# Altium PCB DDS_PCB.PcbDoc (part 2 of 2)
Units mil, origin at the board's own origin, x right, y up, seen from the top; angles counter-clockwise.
Board outline 3998.07 x 3476.44 mil, 8 copper layers (TOP_L1, Plane_L2, Inner_L3, Plane_L4, Plane_L5, Inner_L6, Plane_L7, Bottom Layer_L8), stack 26.8 mil thick; 448 components, 265 nets, 1489 pads, 18 vias.
Unrouted connection lines stored in the file: 996.

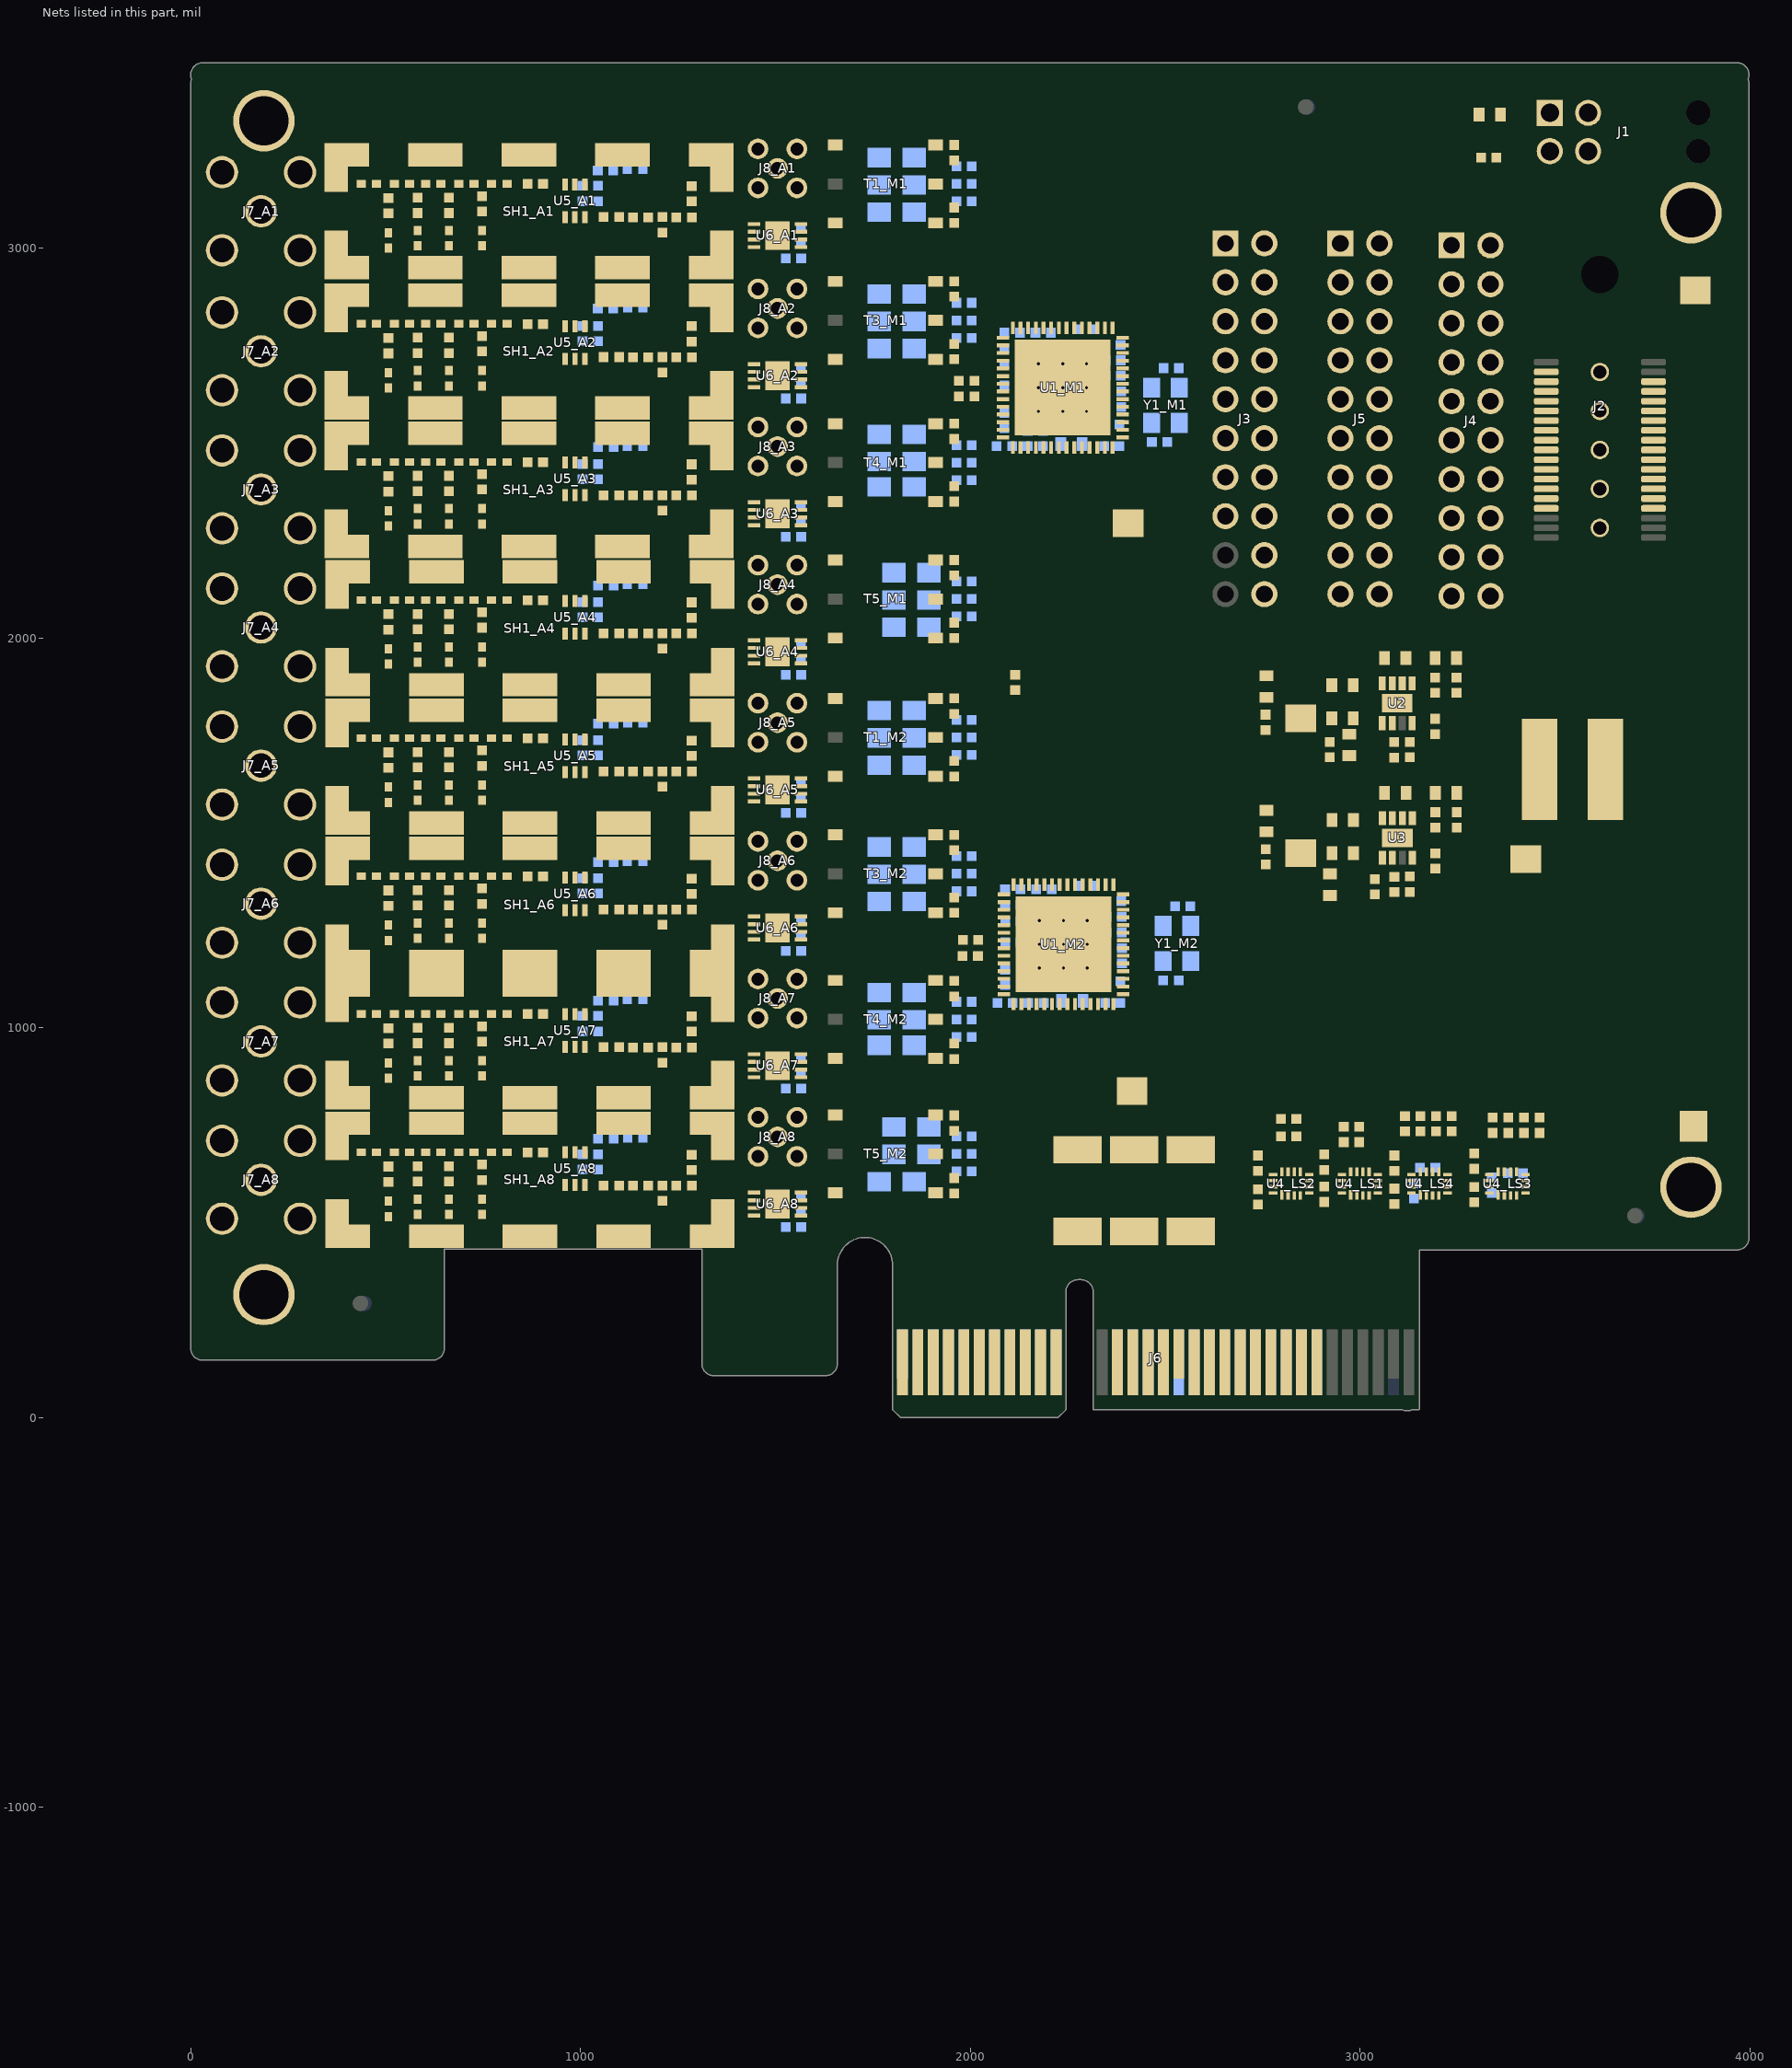
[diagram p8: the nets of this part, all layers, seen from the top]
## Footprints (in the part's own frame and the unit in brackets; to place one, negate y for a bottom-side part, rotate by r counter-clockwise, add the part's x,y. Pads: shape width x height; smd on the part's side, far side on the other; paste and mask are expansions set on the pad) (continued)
PCIE_8LANE_EDGE [mil] "PCIE_8LANE_EDGE"
  rect 28x126 smd far side paste-100: A1(-984.25,-93.98)
  rect 28x169 smd far side paste-100: A2(-944.88,-115.48) A3(-905.51,-115.48) A4(-866.14,-115.48) A5(-826.77,-115.48) A6(-787.4,-115.48) A7(-748.03,-115.48) A8(-708.66,-115.48) A9(-669.29,-115.48) A10(-629.92,-115.48) A11(-590.55,-115.48) A12(-472.44,-115.48) A13(-433.07,-115.48) A14(-393.7,-115.48) A15(-354.33,-115.48) A16(-314.96,-115.48) A17(-275.59,-115.48) A18(-236.22,-115.48) A19(-196.85,-115.48) A20(-157.48,-115.48) A21(-118.11,-115.48) A22(-78.74,-115.48) A23(-39.37,-115.48) A24(0,-115.48) A25(39.37,-115.48) A26(78.74,-115.48) A27(118.11,-115.48) A28(157.48,-115.48) A29(196.85,-115.48) A30(236.22,-115.48) A31(275.59,-115.48) A32(314.96,-115.48)
  rect 28x169 smd paste-100 mask+2: B1(-984.25,-115.48) B2(-944.88,-115.48) B3(-905.51,-115.48) B4(-866.14,-115.48) B5(-826.77,-115.48) B6(-787.4,-115.48) B7(-748.03,-115.48) B8(-708.66,-115.48) B9(-669.29,-115.48) B10(-629.92,-115.48) B11(-590.55,-115.48) B12(-472.44,-115.48) B13(-433.07,-115.48) B14(-393.7,-115.48) B15(-354.33,-115.48) B16(-314.96,-115.48) B18(-236.22,-115.48) B19(-196.85,-115.48) B20(-157.48,-115.48) B21(-118.11,-115.48) B22(-78.74,-115.48) B23(-39.37,-115.48) B24(0,-115.48) B25(39.37,-115.48) B26(78.74,-115.48) B27(118.11,-115.48) B28(157.48,-115.48) B29(196.85,-115.48) B30(236.22,-115.48) B32(314.96,-115.48)
  rect 28x126 smd paste-100 mask+2: B17(-275.59,-93.98) B31(275.59,-93.98)
R0402 [mil] "R0402"
  rect 25x25 smd mask+2: 1(-18.5,0) 2(20.9,0)
  silkscreen extent -36,-17 40,17, body extent -20,-10 20,10, height 14
r0402 [mil] "R0402"
  rect 25x25 smd mask+2: 1(-18.5,0) 2(20.9,0)
  silkscreen extent -36,-17 40,17, body extent -20,-10 20,10, height 14
R0805 [mil] "R0805"
  rect 60x50 smd mask+2: 1(-45,0) 2(45,0)
  silkscreen extent -80,-30 80,30, body extent -39,-25 39,24, height 31
RF_Sh [mil]
  rect 60x125 smd mask+2: 1(-495,-112.5) 1(-495,112.5) 1(495,-112.5) 1(495,112.5)
  rect 115x60 smd mask+2: 1(-467.5,-145) 1(-467.5,145) 1(467.5,-145) 1(467.5,145)
  rect 140x60 smd mask+2: 1(-240,-145) 1(-240,145) 1(0,-145) 1(0,145) 1(240,-145) 1(240,145)
SAMTEC_MMCX-J-P-H-ST-TH1 [mm]
  round 1.348 hole 0.84: 1(0,0) S1(-1.27,1.27) S2(1.27,1.27) S3(1.27,-1.27) S4(-1.27,-1.27)
  silkscreen extent -1.75,-1.75 1.75,1.75, body extent -1.75,-1.75 1.75,1.75, height 4.35
SMD4_ECX-32_3P2X2P5_ECS [mm]
  rect 1.1x1.3 smd paste-0.55 mask+0.051: 1(-0.9,1.15) 2(-0.9,-1.15) 3(0.9,-1.15) 4(0.9,1.15)
  silkscreen extent -1.42,-0.17 1.42,0.17, body extent -1.3,-1.65 1.3,1.65, height 0.81
SO8_MUN12AD_DEA [mm]
  rect 0.91x0.458 smd paste+0 mask+0.051: 1(-1.293,0.975) 2(-1.293,0.325) 3(-1.293,-0.325) 4(-1.293,-0.975) 5(1.293,-0.975) 6(1.293,-0.325) 7(1.293,0.325) 8(1.293,0.975)
  rect 1.2x2 smd paste+0 mask+0.051: 9(0,0)
  silkscreen extent -1.57,-1.68 1.57,1.68, body extent -1.45,-1.55 1.45,1.55, height 1.5
SOT_2815,115_NXP [mm]
  rect 0.782x0.355 smd paste+0 mask+0.051: 1(-1.064,0.65) 2(-1.064,0) 3(-1.064,-0.65) 4(1.064,-0.65) 5(1.064,0) 6(1.064,0.65)
  silkscreen extent -0.8,-1.23 0.8,1.23, body extent -1.1,-1.1 1.1,1.1, height 1.09
TP_2X1.8 [mm]
  rect 1.8x2 smd mask+0.051: 1(0,0)
  body extent -0.89,-0.99 0.89,0.99, height 0.03

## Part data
C1_M1 C1_M2: library part "CAP CER 6.8pF 50V NP0 0402", "CAP CER 680PF 50V NP0 0402", Capacitance=680pF, Manufacturer="TDK Corporation", Manufacturer Part Number=C1005C0G1H6R8D, Package / Case="0402 (1005 Metric)", Voltage - Rated=50V
C2_M1 C2_M2 C3_M1 C3_M2: library part "CAP CER 6.8pF 50V NP0 0402", "CAP CER 39PF 50V NP0 0402", Capacitance=39pF, Manufacturer="TDK Corporation", Manufacturer Part Number=C1005C0G1H6R8D, Package / Case="0402 (1005 Metric)", Voltage - Rated=50V
C4_M1 C4_M2 C5_M1 C5_M2 C6_M1 C6_M2 C31_A1 C31_A2 C31_A3 C31_A4 C31_A5 C31_A6 C31_A7 C31_A8 C32_A1 C32_A2 C32_A3 C32_A4 C32_A5 C32_A6 C32_A7 C32_A8 C40_A1 C40_A2 C40_A3 C40_A4 C40_A5 C40_A6 C40_A7 C40_A8: library part "CAP CER 6.8pF 50V NP0 0402", "CAP CER 1uF 25V X5R 0402", Capacitance=1uF, Manufacturer="TDK Corporation", Manufacturer Part Number=C1005C0G1H6R8D, Package / Case="0402 (1005 Metric)", Voltage - Rated=50V
C7_M1 C7_M2 C8_M1 C8_M2 C9_M1 C9_M2 C43_M1 C43_M2 C59_M1 C59_M2 C62_M1 C62_M2 C65_M1 C65_M2: library part "CAP CER 6.8pF 50V NP0 0402", "CAP CER 10uF 10V X5R 0402", Capacitance=10uF, Manufacturer="TDK Corporation", Manufacturer Part Number=C1005C0G1H6R8D, Package / Case="0402 (1005 Metric)", Voltage - Rated=50V
C10_M1 C10_M2 C11_M1 C11_M2 C12_M1 C12_M2 C29_LS1 C29_LS2 C29_LS3 C29_LS4 C30_LS1 C30_LS2 C30_LS3 C30_LS4 C38_A1 C38_A2 C38_A3 C38_A4 C38_A5 C38_A6 C38_A7 C38_A8 C39_A1 C39_A2 C39_A3 C39_A4 C39_A5 C39_A6 C39_A7 C39_A8 C41_M1 C41_M2 C42_M1 C42_M2 C57_M1 C57_M2 C58_M1 C58_M2 C60_M1 C60_M2 C61_M1 C61_M2 C63_M1 C63_M2 C64_M1 C64_M2: library part "CAP CER 6.8pF 50V NP0 0402", "CAP CER 0.1uF 50V NP0 0402", Capacitance=0.1uF, Manufacturer="TDK Corporation", Manufacturer Part Number=C1005C0G1H6R8D, Package / Case="0402 (1005 Metric)", Voltage - Rated=50V
C13 C20 C26: library part "CAP CER 10uF 10V 10% X5R 0603", "CAP CER 10UF 25V 10% X5R 0603", Capacitance=10µF, Manufacturer="TDK Corporation", Manufacturer Part Number=C1608X5R1A106K, Package / Case="0603 (1608 Metric)", Voltage - Rated=10V
C14 C15 C18 C19 C22 C24 C25: library part "CAP CER 12nF 25V 10% X7R 0402", "CAP CER 10nF 25V 10% X5R 0402", Capacitance=10nF, Manufacturer="Murata Electronics North America", Manufacturer Part Number=GRM155R71E123KA61D, Package / Case="0402 (1005 Metric)", Voltage - Rated=25V
C16 C17 C23 C27: library part "CAP CER 10uF 10V 10% X5R 0603", "CAP CER 22UF 16V 10% X5R 0603", Capacitance=22µF, Manufacturer="TDK Corporation", Manufacturer Part Number=C1608X5R1A106K, Package / Case="0603 (1608 Metric)", Voltage - Rated=10V
C21 C28: library part "CAP CER 6.8pF 50V NP0 0402", "CAP CER NA 50V NP0 0402", Manufacturer="TDK Corporation", Manufacturer Part Number=C1005C0G1H6R8D, Package / Case="0402 (1005 Metric)", Voltage - Rated=50V
C33_A1 C33_A2 C33_A3 C33_A4 C33_A5 C33_A6 C33_A7 C33_A8: library part "CAP CER 20pF 50V 5% NP0 0402", "CAP CER 16PF 50V 5% NP0 0402", Capacitance=16pF, Manufacturer="TDK Corporation", Manufacturer Part Number=C1005C0G1H200J, Package / Case="0402 (1005 Metric)", Voltage - Rated=50V
C34_A1 C34_A2 C34_A3 C34_A4 C34_A5 C34_A6 C34_A7 C34_A8: library part "CAP CER 20pF 50V 5% NP0 0402", "CAP CER 11PF 50V 5% NP0 0402", Capacitance=11pF, Manufacturer="TDK Corporation", Manufacturer Part Number=C1005C0G1H200J, Package / Case="0402 (1005 Metric)", Voltage - Rated=50V
C35_A1 C35_A2 C35_A3 C35_A4 C35_A5 C35_A6 C35_A7 C35_A8: library part "CAP CER 20pF 50V 5% NP0 0402", "CAP CER 10PF 50V 5% NP0 0402", Capacitance=10pF, Manufacturer="TDK Corporation", Manufacturer Part Number=C1005C0G1H200J, Package / Case="0402 (1005 Metric)", Voltage - Rated=50V
C36_A1 C36_A2 C36_A3 C36_A4 C36_A5 C36_A6 C36_A7 C36_A8: library part "CAP CER 20pF 50V 5% NP0 0402", "CAP CER 13PF 50V 5% NP0 0402", Capacitance=13pF, Manufacturer="TDK Corporation", Manufacturer Part Number=C1005C0G1H200J, Package / Case="0402 (1005 Metric)", Voltage - Rated=50V
C37_A1 C37_A2 C37_A3 C37_A4 C37_A5 C37_A6 C37_A7 C37_A8: library part "CAP CER 6.8pF 50V NP0 0402", "CAP CER 470pF 25V X5R 0402", Capacitance=470pF, Manufacturer="TDK Corporation", Manufacturer Part Number=C1005C0G1H6R8D, Package / Case="0402 (1005 Metric)", Voltage - Rated=50V
F1 F2 F3: library part 1812L150/24MR, "FUSE PTC 24V 1.5A POLYFUSE 1812", Current - Hold (Ih) (Max)=1.5A, Manufacturer="Littelfuse Inc", Package / Case="1812 (4532 Metric), Concave"
FB1_M1 FB1_M2 FB2 FB3 FB4 FB5: library part BK1608HS600-T, "FERRITE BEAD 220_OHM@100MHz 0603 2A 50mohm_DC", Manufacturer="Taiyo Yuden", Package / Case="0603 (1608 Metric)"
FB6_A1 FB6_A2 FB6_A3 FB6_A4 FB6_A5 FB6_A6 FB6_A7 FB6_A8: library part BK1608HS600-T, "FERRITE BEAD 1.8K OHM 0402 1LN", Manufacturer="Taiyo Yuden", Package / Case="0603 (1608 Metric)"
H1 H2 H3 H4: "hole 3mm"
J1: "No Description Available", Mfr_Name="Molex Connector Corporation"
J2: "CONN MICTOR 38POS .025 VERT SMD", Manufacturer="TE Connectivity"
J3 J4 J5: "CONN HEADER 20 TH", Manufacturer="Molex Connector Corporation"
J6: "64 Position Female Connector PCI Expressâ„¢ Gold 0.039 _1.00mm_ Black", Package=None
J7_A1 J7_A2 J7_A3 J7_A4 J7_A5 J7_A6 J7_A7 J7_A8: "No Description Available", Mfr_Name="Samtec Inc"
J8_A1 J8_A2 J8_A3 J8_A4 J8_A5 J8_A6 J8_A7 J8_A8: "MMCX STRAIGHT, THROUGH HOLE JACK- 50 OHM", Package=None
LD1 LD2: "LED 1.6X0.8MM 568NM GRN CLR SMD", Manufacturer="Kingbright Corp", Package / Case="0603 (1608 Metric)"
Lp1: "INDUCTOR 10UH 1.9A 20% SMD", Manufacturer="Taiyo Yuden", Package / Case="Non Standard"
R1_M1 R1_M2: library part "RES 3.09K OHM 1/16W 1% 0402", "RES 6.8K OHM 1/16W 1% 0402", Manufacturer="Stackpole Electronics Inc", Manufacturer Part Number=RMCF0402FT3K09, Package / Case="0402 (1005 Metric)", Power (Watts)="0.063W, 1/16W", Supplier Device Package=0402
R2_M1 R2_M2 R7_M1 R7_M2 R8_M1 R8_M2 R9_M1 R9_M2 R10_M1 R10_M2 R33 R41_A1 R41_A2 R41_A3 R41_A4 R41_A5 R41_A6 R41_A7 R41_A8: library part "RES 100 OHM 1/10W 1% 0402 SMD", "RES 0 OHM 1/10W 1% 0402 SMD", Manufacturer="Panasonic Electronic Components", Manufacturer Part Number=ERJ-2RKF1000X, Package / Case="0402 (1005 Metric)", Supplier Device Package=0402
R3_M1 R3_M2 R4_M1 R4_M2 R5_M1 R5_M2 R6_M1 R6_M2 R11_M1 R11_M2 R12_M1 R12_M2 R13_M1 R13_M2 R14_M1 R14_M2: library part "RES 3.09K OHM 1/16W 1% 0402", "RES 10K OHM 1/16W 1% 0402", Manufacturer="Stackpole Electronics Inc", Manufacturer Part Number=RMCF0402FT3K09, Package / Case="0402 (1005 Metric)", Power (Watts)="0.063W, 1/16W", Supplier Device Package=0402
R15_M1 R15_M2 R16_M1 R16_M2 R17_M1 R17_M2 R18_M1 R18_M2 R19_M1 R19_M2 R20_M1 R20_M2 R21_M1 R21_M2 R22_M1 R22_M2 R23_M1 R23_M2 R24_M1 R24_M2 R25_M1 R25_M2 R26_M1 R26_M2: library part "RES 200 OHM 1/8W 1% 0805 SMD", "RES 0 OHM 1/8W 1% 0805 SMD", Manufacturer="Stackpole Electronics Inc", Manufacturer Part Number=RMCF0805FT200R, Package / Case="0805 (2012 Metric)", Power (Watts)="0.125W, 1/8W", Supplier Device Package=0805
R27 R30: library part "RES 15.4K OHM 1/10W 1% 0402 SMD", "RES 124K OHM 1/10W 1% 0402 SMD", Manufacturer="Panasonic Electronic Components", Manufacturer Part Number=ERJ-2RKF1542X, Package / Case="0402 (1005 Metric)", Power (Watts)="0.1W, 1/10W", Supplier Device Package=0402
R28 R31: library part "RES 3.09K OHM 1/16W 1% 0402", "RES 1K OHM 1/16W 1% 0402", Manufacturer="Stackpole Electronics Inc", Manufacturer Part Number=RMCF0402FT3K09, Package / Case="0402 (1005 Metric)", Power (Watts)="0.063W, 1/16W", Supplier Device Package=0402
R29: library part "RES 15.4K OHM 1/10W 1% 0402 SMD", "RES 39.2K OHM 1/10W 1% 0402 SMD", Manufacturer="Panasonic Electronic Components", Manufacturer Part Number=ERJ-2RKF1542X, Package / Case="0402 (1005 Metric)", Power (Watts)="0.1W, 1/10W", Supplier Device Package=0402
R32 R34_LS1 R34_LS2 R34_LS3 R34_LS4: library part "RES 3.09K OHM 1/16W 1% 0402", "RES 100K OHM 1/16W 1% 0402", Manufacturer="Stackpole Electronics Inc", Manufacturer Part Number=RMCF0402FT3K09, Package / Case="0402 (1005 Metric)", Power (Watts)="0.063W, 1/16W", Supplier Device Package=0402
R35_LS1 R35_LS2 R35_LS3 R35_LS4: library part "RES 3.09K OHM 1/16W 1% 0402", "RES 3.09K OHM 1/16W 1% 0402", Manufacturer="Stackpole Electronics Inc", Manufacturer Part Number=RMCF0402FT3K09, Package / Case="0402 (1005 Metric)", Power (Watts)="0.063W, 1/16W", Supplier Device Package=0402
R36_A1 R36_A2 R36_A3 R36_A4 R36_A5 R36_A6 R36_A7 R36_A8 R37_A1 R37_A2 R37_A3 R37_A4 R37_A5 R37_A6 R37_A7 R37_A8: library part "RES 100 OHM 1/10W 1% 0402 SMD", "RES 34.8 OHM 1/10W 1% 0402 SMD", Manufacturer="Panasonic Electronic Components", Manufacturer Part Number=ERJ-2RKF1000X, Package / Case="0402 (1005 Metric)", Supplier Device Package=0402
R38_A1 R38_A2 R38_A3 R38_A4 R38_A5 R38_A6 R38_A7 R38_A8 R42_A1 R42_A2 R42_A3 R42_A4 R42_A5 R42_A6 R42_A7 R42_A8: library part "RES 100 OHM 1/10W 1% 0402 SMD", "RES 18.2 OHM 1/10W 1% 0402 SMD", Manufacturer="Panasonic Electronic Components", Manufacturer Part Number=ERJ-2RKF1000X, Package / Case="0402 (1005 Metric)", Supplier Device Package=0402
R39_M1 R39_M2 R40_M1 R40_M2 R50_M1 R50_M2 R51_M1 R51_M2 R52_M1 R52_M2 R53_M1 R53_M2 R54_M1 R54_M2 R55_M1 R55_M2: library part "RES 100 OHM 1/10W 1% 0402 SMD", "RES 49.9 OHM 1/10W 1% 0402 SMD", Manufacturer="Panasonic Electronic Components", Manufacturer Part Number=ERJ-2RKF1000X, Package / Case="0402 (1005 Metric)", Supplier Device Package=0402
SH1_A1 SH1_A2 SH1_A3 SH1_A4 SH1_A5 SH1_A6 SH1_A7 SH1_A8: library part RF_SHIELD_1, "RF Shield Cover 0.300\" (7.62mm) X 1.000\" (25.40mm) Non-Vented Surface Mount", Manufacturer="Orbel Corporation"
T1_M1 T1_M2 T3_M1 T3_M2 T4_M1 T4_M2 T5_M1 T5_M2: "No Description Available", Mfr_Name="Mini Circuits"
TP1 TP2 TP3 TP4 TP5 TP6: library part "TP mini_2", "TP PC MINIATURE SMT", Manufacturer="Keystone Electronics", Manufacturer Part Number=5015
TP7: library part "TP mini_1", "TP PC MINIATURE SMT", Manufacturer="Keystone Electronics", Manufacturer Part Number=5015
U1_M1 U1_M2 U6_A1 U6_A2 U6_A3 U6_A4 U6_A5 U6_A6 U6_A7 U6_A8: "No Description Available", Mfr_Name="Analog Devices Inc"
U2 U3: "No Description Available", Mfr_Name=Delta
U5_A1 U5_A2 U5_A3 U5_A4 U5_A5 U5_A6 U5_A7 U5_A8: "No Description Available", Mfr_Name=NXP
Y1_M1 Y1_M2: "No Description Available", Mfr_Name="ECS International"

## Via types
v1: diameter 16, hole 8, TOP_L1 to Bottom Layer_L8, tented both sides, 18 vias

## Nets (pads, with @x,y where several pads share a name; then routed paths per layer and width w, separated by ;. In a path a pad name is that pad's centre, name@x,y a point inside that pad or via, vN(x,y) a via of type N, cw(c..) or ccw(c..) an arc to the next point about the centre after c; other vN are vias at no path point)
1.8V: C23.2 C27.2 FB5.1 R30.2 U3.4 U3.5
1_8V: F2.1 J6.B5 J6.B6 J6.B7 J6.B8
3.3V: C16.2 C17.2 FB3.1 R27.2 U2.4 U2.5
3.3V_AMP_A1: C37_A1.2 C38_A1.2 R42_A1.2 U5_A1.1
3.3V_AMP_A2: C37_A2.2 C38_A2.2 R42_A2.2 U5_A2.1
3.3V_AMP_A3: C37_A3.2 C38_A3.2 R42_A3.2 U5_A3.1
3.3V_AMP_A4: C37_A4.2 C38_A4.2 R42_A4.2 U5_A4.1
3.3V_AMP_A5: C37_A5.2 C38_A5.2 R42_A5.2 U5_A5.1
3.3V_AMP_A6: C37_A6.2 C38_A6.2 R42_A6.2 U5_A6.1
3.3V_AMP_A7: C37_A7.2 C38_A7.2 R42_A7.2 U5_A7.1
3.3V_AMP_A8: C37_A8.2 C38_A8.2 R42_A8.2 U5_A8.1
3_3V: F1.1 J6.B1 J6.B2 J6.B3 J6.B4
12_V: F3.2 J6.A1 J6.A2 J6.A3 J6.A4
12v_1: C19.2 C20.2 FB2.2 U2.1 U2.2
12v_2: C25.2 C26.2 FB4.2 U3.1 U3.2
12v_in: C13.2 C14.2 J1.1 J1.2 Lp1.1
AVDD0_M1: C41_M1.2 C42_M1.2 C43_M1.2 R18_M1.2 R22_M1.2 R26_M1.2 R39_M1.2 R40_M1.1 T1_M1.2
AVDD0_M2: C41_M2.2 C42_M2.2 C43_M2.2 R18_M2.2 R22_M2.2 R26_M2.2 R39_M2.2 R40_M2.1 T1_M2.2
AVDD1_M1: C57_M1.2 C58_M1.2 C59_M1.2 R17_M1.2 R18_M1.1 R21_M1.2 R22_M1.1 R25_M1.2 R26_M1.1 R50_M1.2 R51_M1.1 T3_M1.2
AVDD1_M2: C57_M2.2 C58_M2.2 C59_M2.2 R17_M2.2 R18_M2.1 R21_M2.2 R22_M2.1 R25_M2.2 R26_M2.1 R50_M2.2 R51_M2.1 T3_M2.2
AVDD2_M1: C60_M1.2 C61_M1.2 C62_M1.2 R16_M1.2 R17_M1.1 R20_M1.2 R21_M1.1 R24_M1.2 R25_M1.1 R52_M1.2 R53_M1.1 T4_M1.2
AVDD2_M2: C60_M2.2 C61_M2.2 C62_M2.2 R16_M2.2 R17_M2.1 R20_M2.2 R21_M2.1 R24_M2.2 R25_M2.1 R52_M2.2 R53_M2.1 T4_M2.2
AVDD3_M1: C63_M1.2 C64_M1.2 C65_M1.2 R15_M1.2 R16_M1.1 R19_M1.2 R20_M1.1 R23_M1.2 R24_M1.1 R54_M1.2 R55_M1.1 T5_M1.2
AVDD3_M2: C63_M2.2 C64_M2.2 C65_M2.2 R15_M2.2 R16_M2.1 R19_M2.2 R20_M2.1 R23_M2.2 R24_M2.1 R54_M2.2 R55_M2.1 T5_M2.2
CH0_M1_N: R40_M1.2 T1_M1.3 U1_M1.29
CH0_M1_P: R39_M1.1 T1_M1.1 U1_M1.30
CH0_M2_N: R40_M2.2 T1_M2.3 U1_M2.29
CH0_M2_P: R39_M2.1 T1_M2.1 U1_M2.30
CH1_M1_N: R51_M1.2 T3_M1.3 U1_M1.35
CH1_M1_P: R50_M1.1 T3_M1.1 U1_M1.36
CH1_M2_N: R51_M2.2 T3_M2.3 U1_M2.35
CH1_M2_P: R50_M2.1 T3_M2.1 U1_M2.36
CH2_M1_N: R53_M1.2 T4_M1.1 U1_M1.9
CH2_M1_P: R52_M1.1 T4_M1.3 U1_M1.8
CH2_M2_N: R53_M2.2 T4_M2.1 U1_M2.9
CH2_M2_P: R52_M2.1 T4_M2.3 U1_M2.8
CH3_M1_N: R55_M1.2 T5_M1.1 U1_M1.14
CH3_M1_P: R54_M1.1 T5_M1.3 U1_M1.13
CH3_M2_N: R55_M2.2 T5_M2.1 U1_M2.14
CH3_M2_P: R54_M2.1 T5_M2.3 U1_M2.13
CLK_sel_M1: R8_M1.1 R10_M1.2 U1_M1.24
CLK_sel_M2: R8_M2.1 R10_M2.2 U1_M2.24
contr0_M1: J2.26 J3.1 J6.B13 U6_A1.2
contr0_M2: J2.25 J3.9 J6.A13 U6_A5.2
contr1_M1: J2.28 J3.3 J6.B14 U6_A2.2
contr1_M2: J2.27 J3.11 J6.A14 U6_A6.2
contr2_M1: J2.30 J3.5 J6.B15 U6_A3.2
contr2_M2: J2.29 J3.13 J6.A15 U6_A7.2
contr3_M1: J2.32 J3.7 J6.B16 U6_A4.2
contr3_M2: J2.31 J3.15 J6.A16 U6_A8.2
CSn: U1_M1.47 U4_LS2.12
CSn_2: U1_M2.47 U4_LS1.12
CSn_2_L: J2.7 J5.3 J6.A18 U4_LS1.1
CSn_L: J2.8 J4.3 J6.B18 U4_LS2.1
DAC_O0_M1: T1_M1.6 U6_A1.4
DAC_O0_M2: T1_M2.6 U6_A5.4
DAC_O1_M1: T3_M1.6 U6_A2.4
DAC_O1_M2: T3_M2.6 U6_A6.4
DAC_O2_M1: T4_M1.4 U6_A3.4
DAC_O2_M2: T4_M2.4 U6_A7.4
DAC_O3_M1: T5_M1.4 U6_A4.4
DAC_O3_M2: T5_M2.4 U6_A8.4
DIR_LS1: J2.21 J5.17 J6.A25 R34_LS1.1 R34_LS4.1 R35_LS1.2 R35_LS4.2 U4_LS1.5 U4_LS1.6 U4_LS1.15 U4_LS1.16 U4_LS4.5 U4_LS4.6 U4_LS4.15 U4_LS4.16
DIR_LS2: J2.22 J4.17 J6.B25 R34_LS2.1 R34_LS3.1 R35_LS2.2 R35_LS3.2 U4_LS2.5 U4_LS2.6 U4_LS2.15 U4_LS2.16 U4_LS3.5 U4_LS3.6 U4_LS3.15 U4_LS3.16
FB_1.8: R30.1 R32.2 U3.6
FB_3.3: R27.1 R29.2 U2.6
GND: C2_M1.2 C2_M2.2 C3_M1.1 C3_M2.1 C4_M1.1 C4_M2.1 C5_M1.1 C5_M2.1 C6_M1.1 C6_M2.1 C7_M1.1 C7_M2.1 C8_M1.1 C8_M2.1 C9_M1.1 C9_M2.1 C10_M1.1 C10_M2.1 C11_M1.1 C11_M2.1 C12_M1.1 C12_M2.1 C13.1 C14.1 C15.1 C16.1 C17.1 C18.1 C19.1 C20.1 C21.1 C22.1 C23.1 C24.1 C25.1 C26.1 C27.1 C28.1 C29_LS1.1 C29_LS2.1 C29_LS3.1 C29_LS4.1 C30_LS1.1 C30_LS2.1 C30_LS3.1 C30_LS4.1 C37_A1.1 C37_A2.1 C37_A3.1 C37_A4.1 C37_A5.1 C37_A6.1 C37_A7.1 C37_A8.1 C38_A1.1 C38_A2.1 C38_A3.1 C38_A4.1 C38_A5.1 C38_A6.1 C38_A7.1 C38_A8.1 C39_A1.1 C39_A2.1 C39_A3.1 C39_A4.1 C39_A5.1 C39_A6.1 C39_A7.1 C39_A8.1 C40_A1.1 C40_A2.1 C40_A3.1 C40_A4.1 C40_A5.1 C40_A6.1 C40_A7.1 C40_A8.1 C41_M1.1 C41_M2.1 C42_M1.1 C42_M2.1 C43_M1.1 C43_M2.1 C57_M1.1 C57_M2.1 C58_M1.1 C58_M2.1 C59_M1.1 C59_M2.1 C60_M1.1 C60_M2.1 C61_M1.1 C61_M2.1 C62_M1.1 C62_M2.1 C63_M1.1 C63_M2.1 C64_M1.1 C64_M2.1 C65_M1.1 C65_M2.1 H1.1 H2.1 H3.1 H4.1 J1.3 J1.4 J2.3 J2.39 J2.40 J2.41 J2.42 J2.43 J3.2 J3.4 J3.6 J3.8 J3.10 J3.12 J3.14 J3.16 J3.18 J3.20 J4.2 J4.4 J4.6 J4.8 J4.10 J4.12 J4.14 J4.16 J4.18 J4.20 J5.2 J5.4 J5.6 J5.8 J5.10 J5.12 J5.14 J5.16 J5.18 J5.20 J6.A5 J6.A6 J6.A7 J6.A8 J6.A9 J6.A10 J6.A11 J6.B9 J6.B10 J6.B11 J7_A1.2 J7_A1.3 J7_A1.4 J7_A1.5 J7_A2.2 J7_A2.3 J7_A2.4 J7_A2.5 J7_A3.2 J7_A3.3 J7_A3.4 J7_A3.5 J7_A4.2 J7_A4.3 J7_A4.4 J7_A4.5 J7_A5.2 J7_A5.3 J7_A5.4 J7_A5.5 J7_A6.2 J7_A6.3 J7_A6.4 J7_A6.5 J7_A7.2 J7_A7.3 J7_A7.4 J7_A7.5 J7_A8.2 J7_A8.3 J7_A8.4 J7_A8.5 J8_A1.S1 J8_A1.S2 J8_A1.S3 J8_A1.S4 J8_A2.S1 J8_A2.S2 J8_A2.S3 J8_A2.S4 J8_A3.S1 J8_A3.S2 J8_A3.S3 J8_A3.S4 J8_A4.S1 J8_A4.S2 J8_A4.S3 J8_A4.S4 J8_A5.S1 J8_A5.S2 J8_A5.S3 J8_A5.S4 J8_A6.S1 J8_A6.S2 J8_A6.S3 J8_A6.S4 J8_A7.S1 J8_A7.S2 J8_A7.S3 J8_A7.S4 J8_A8.S1 J8_A8.S2 J8_A8.S3 J8_A8.S4 L6_A1.2 L6_A2.2 L6_A3.2 L6_A4.2 L6_A5.2 L6_A6.2 L6_A7.2 L6_A8.2 L7_A1.2 L7_A2.2 L7_A3.2 L7_A4.2 L7_A5.2 L7_A6.2 L7_A7.2 L7_A8.2 L8_A1.2 L8_A2.2 L8_A3.2 L8_A4.2 L8_A5.2 L8_A6.2 L8_A7.2 L8_A8.2 L9_A1.2 L9_A2.2 L9_A3.2 L9_A4.2 L9_A5.2 L9_A6.2 L9_A7.2 L9_A8.2 LD1.2 LD2.2 R1_M1.1 R1_M2.1 R3_M1.1 R3_M2.1 R4_M1.1 R4_M2.1 R5_M1.1 R5_M2.1 R6_M1.1 R6_M2.1 R9_M1.1 R9_M2.1 R10_M1.1 R10_M2.1 R11_M1.1 R11_M2.1 R12_M1.1 R12_M2.1 R13_M1.1 R13_M2.1 R14_M1.1 R14_M2.1 R29.1 R32.1 R35_LS1.1 R35_LS2.1 R35_LS3.1 R35_LS4.1 R38_A1.2 R38_A2.2 R38_A3.2 R38_A4.2 R38_A5.2 R38_A6.2 R38_A7.2 R38_A8.2 SH1_A1.1 SH1_A2.1 SH1_A3.1 SH1_A4.1 SH1_A5.1 SH1_A6.1 SH1_A7.1 SH1_A8.1 T1_M1.4 T1_M2.4 T3_M1.4 T3_M2.4 T4_M1.6 T4_M2.6 T5_M1.6 T5_M2.6 TP6.1 TP7.1 U1_M1.6 U1_M1.10 U1_M1.12 U1_M1.16 U1_M1.18 U1_M1.20 U1_M1.25 U1_M1.28 U1_M1.32 U1_M1.34 U1_M1.38 U1_M1.44 U1_M1.56 U1_M1.57 U1_M2.6 U1_M2.10 U1_M2.12 U1_M2.16 U1_M2.18 U1_M2.20 U1_M2.25 U1_M2.28 U1_M2.32 U1_M2.34 U1_M2.38 U1_M2.44 U1_M2.56 U1_M2.57 U2.3 U2.9 U3.3 U3.9 U4_LS1.7 U4_LS1.8 U4_LS2.7 U4_LS2.8 U4_LS3.7 U4_LS3.8 U4_LS4.7 U4_LS4.8 U5_A1.2 U5_A1.4 U5_A1.5 U5_A2.2 U5_A2.4 U5_A2.5 U5_A3.2 U5_A3.4 U5_A3.5 U5_A4.2 U5_A4.4 U5_A4.5 U5_A5.2 U5_A5.4 U5_A5.5 U5_A6.2 U5_A6.4 U5_A6.5 U5_A7.2 U5_A7.4 U5_A7.5 U5_A8.2 U5_A8.4 U5_A8.5 U6_A1.3 U6_A1.5 U6_A1.6 U6_A1.7 U6_A1.9 U6_A2.3 U6_A2.5 U6_A2.6 U6_A2.7 U6_A2.9 U6_A3.3 U6_A3.5 U6_A3.6 U6_A3.7 U6_A3.9 U6_A4.3 U6_A4.5 U6_A4.6 U6_A4.7 U6_A4.9 U6_A5.3 U6_A5.5 U6_A5.6 U6_A5.7 U6_A5.9 U6_A6.3 U6_A6.5 U6_A6.6 U6_A6.7 U6_A6.9 U6_A7.3 U6_A7.5 U6_A7.6 U6_A7.7 U6_A7.9 U6_A8.3 U6_A8.5 U6_A8.6 U6_A8.7 U6_A8.9 Y1_M1.2 Y1_M1.4 Y1_M2.2 Y1_M2.4
  other v1: 2176.9,1153.11 2238.9,1153.11 2299.9,1153.11 2176.9,1214.11 2238.9,1214.11 2299.9,1214.11 2176.9,1275.11 2238.9,1275.11 2299.9,1275.11 2174.85,2581.52 2236.85,2581.52 2297.85,2581.52 2174.85,2642.52 2236.85,2642.52 2297.85,2642.52 2174.85,2703.52 2236.85,2703.52 2297.85,2703.52
IO_UPDATE: U1_M1.46 U4_LS2.10
IO_UPDATE_2: U1_M2.46 U4_LS1.10
IO_UPDATE_2_L: J2.9 J5.1 J6.A19 U4_LS1.3
IO_UPDATE_L: J2.10 J4.1 J6.B19 U4_LS2.3
MASTER_RESET: U1_M1.3 U4_LS2.9
MASTER_RESET_2: U1_M2.3 U4_LS1.9
MASTER_RESET_2_L: J2.11 J5.7 J6.A20 U4_LS1.4
MASTER_RESET_L: J2.12 J4.7 J6.B20 U4_LS2.4
NetC1_M1_2: C1_M1.2 R2_M1.2
NetC1_M2_2: C1_M2.2 R2_M2.2
NetC21_2: C21.2 U2.8
NetC28_2: C28.2 U3.8
NetFB6_A1_2: FB6_A1.2 R42_A1.1
NetFB6_A2_2: FB6_A2.2 R42_A2.1
NetFB6_A3_2: FB6_A3.2 R42_A3.1
NetFB6_A4_2: FB6_A4.2 R42_A4.1
NetFB6_A5_2: FB6_A5.2 R42_A5.1
NetFB6_A6_2: FB6_A6.2 R42_A6.1
NetFB6_A7_2: FB6_A7.2 R42_A7.1
NetFB6_A8_2: FB6_A8.2 R42_A8.1
NetJ8_A1_1: J8_A1.1 R41_A1.1
NetJ8_A2_1: J8_A2.1 R41_A2.1
NetJ8_A3_1: J8_A3.1 R41_A3.1
NetJ8_A4_1: J8_A4.1 R41_A4.1
NetJ8_A5_1: J8_A5.1 R41_A5.1
NetJ8_A6_1: J8_A6.1 R41_A6.1
NetJ8_A7_1: J8_A7.1 R41_A7.1
NetJ8_A8_1: J8_A8.1 R41_A8.1
NetLD1_1: LD1.1 R28.1
NetLD2_1: LD2.1 R31.1
NetR1_M1_2: R1_M1.2 U1_M1.17
NetR1_M2_2: R1_M2.2 U1_M2.17
NetR2_M1_1: R2_M1.1 U1_M1.27
NetR2_M2_1: R2_M2.1 U1_M2.27
P0_M1: R11_M1.2 U1_M1.40
P0_M2: R11_M2.2 U1_M2.40
P1.8V_ana_M1: C1_M1.1 C1_M2.1 C6_M1.2 C6_M2.2 C9_M1.2 C9_M2.2 C12_M1.2 C12_M2.2 FB1_M1.2 FB1_M2.2 R8_M1.2 R8_M2.2 R15_M1.1 R15_M2.1 R19_M1.1 R19_M2.1 R23_M1.1 R23_M2.1 U1_M1.5 U1_M1.7 U1_M1.11 U1_M1.15 U1_M1.19 U1_M1.21 U1_M1.26 U1_M1.31 U1_M1.33 U1_M1.37 U1_M1.39 U1_M2.5 U1_M2.7 U1_M2.11 U1_M2.15 U1_M2.19 U1_M2.21 U1_M2.26 U1_M2.31 U1_M2.33 U1_M2.37 U1_M2.39
P1_M1: R12_M1.2 U1_M1.41
P1_M2: R12_M2.2 U1_M2.41
P2_M1: R13_M1.2 U1_M1.42
P2_M2: R13_M2.2 U1_M2.42
P3_M1: R14_M1.2 U1_M1.43
P3_M2: R14_M2.2 U1_M2.43
P12V: C15.2 C22.2 F3.1 FB2.1 FB4.1 Lp1.2 TP1.1
PWR_DWN_CTR_M1: R7_M1.1 R9_M1.2 U1_M1.4
PWR_DWN_CTR_M2: R7_M2.1 R9_M2.2 U1_M2.4
REF_CLK_M1_N: C3_M1.2 U1_M1.22 Y1_M1.1
REF_CLK_M1_P: C2_M1.1 U1_M1.23 Y1_M1.3
REF_CLK_M2_N: C3_M2.2 U1_M2.22 Y1_M2.1
REF_CLK_M2_P: C2_M2.1 U1_M2.23 Y1_M2.3
RF_2_A1: C33_A1.1 L1_A1.1 L2_A1.2
RF_2_A2: C33_A2.1 L1_A2.1 L2_A2.2
RF_2_A3: C33_A3.1 L1_A3.1 L2_A3.2
RF_2_A4: C33_A4.1 L1_A4.1 L2_A4.2
RF_2_A5: C33_A5.1 L1_A5.1 L2_A5.2
RF_2_A6: C33_A6.1 L1_A6.1 L2_A6.2
RF_2_A7: C33_A7.1 L1_A7.1 L2_A7.2
RF_2_A8: C33_A8.1 L1_A8.1 L2_A8.2
RF_3_A1: C34_A1.1 L1_A1.2 L3_A1.1
RF_3_A2: C34_A2.1 L1_A2.2 L3_A2.1
RF_3_A3: C34_A3.1 L1_A3.2 L3_A3.1
RF_3_A4: C34_A4.1 L1_A4.2 L3_A4.1
RF_3_A5: C34_A5.1 L1_A5.2 L3_A5.1
RF_3_A6: C34_A6.1 L1_A6.2 L3_A6.1
RF_3_A7: C34_A7.1 L1_A7.2 L3_A7.1
RF_3_A8: C34_A8.1 L1_A8.2 L3_A8.1
RF_4_A1: C35_A1.1 L3_A1.2 L4_A1.1
RF_4_A2: C35_A2.1 L3_A2.2 L4_A2.1
RF_4_A3: C35_A3.1 L3_A3.2 L4_A3.1
RF_4_A4: C35_A4.1 L3_A4.2 L4_A4.1
RF_4_A5: C35_A5.1 L3_A5.2 L4_A5.1
RF_4_A6: C35_A6.1 L3_A6.2 L4_A6.1
RF_4_A7: C35_A7.1 L3_A7.2 L4_A7.1
RF_4_A8: C35_A8.1 L3_A8.2 L4_A8.1
RF_5_A1: C36_A1.1 L4_A1.2 L5_A1.1
RF_5_A2: C36_A2.1 L4_A2.2 L5_A2.1
RF_5_A3: C36_A3.1 L4_A3.2 L5_A3.1
RF_5_A4: C36_A4.1 L4_A4.2 L5_A4.1
RF_5_A5: C36_A5.1 L4_A5.2 L5_A5.1
RF_5_A6: C36_A6.1 L4_A6.2 L5_A6.1
RF_5_A7: C36_A7.1 L4_A7.2 L5_A7.1
RF_5_A8: C36_A8.1 L4_A8.2 L5_A8.1
RF_6_A1: C33_A1.2 L9_A1.1
RF_6_A2: C33_A2.2 L9_A2.1
RF_6_A3: C33_A3.2 L9_A3.1
RF_6_A4: C33_A4.2 L9_A4.1
RF_6_A5: C33_A5.2 L9_A5.1
RF_6_A6: C33_A6.2 L9_A6.1
RF_6_A7: C33_A7.2 L9_A7.1
RF_6_A8: C33_A8.2 L9_A8.1
RF_7_A1: C34_A1.2 L6_A1.1
RF_7_A2: C34_A2.2 L6_A2.1
RF_7_A3: C34_A3.2 L6_A3.1
RF_7_A4: C34_A4.2 L6_A4.1
RF_7_A5: C34_A5.2 L6_A5.1
RF_7_A6: C34_A6.2 L6_A6.1
RF_7_A7: C34_A7.2 L6_A7.1
RF_7_A8: C34_A8.2 L6_A8.1
RF_8_A1: C35_A1.2 L7_A1.1
RF_8_A2: C35_A2.2 L7_A2.1
RF_8_A3: C35_A3.2 L7_A3.1
RF_8_A4: C35_A4.2 L7_A4.1
RF_8_A5: C35_A5.2 L7_A5.1
RF_8_A6: C35_A6.2 L7_A6.1
RF_8_A7: C35_A7.2 L7_A7.1
RF_8_A8: C35_A8.2 L7_A8.1
RF_9_A1: C36_A1.2 L8_A1.1
RF_9_A2: C36_A2.2 L8_A2.1
RF_9_A3: C36_A3.2 L8_A3.1
RF_9_A4: C36_A4.2 L8_A4.1
RF_9_A5: C36_A5.2 L8_A5.1
RF_9_A6: C36_A6.2 L8_A6.1
RF_9_A7: C36_A7.2 L8_A7.1
RF_9_A8: C36_A8.2 L8_A8.1
RF_10_A1: R36_A1.1 R37_A1.2 R38_A1.1
RF_10_A2: R36_A2.1 R37_A2.2 R38_A2.1
RF_10_A3: R36_A3.1 R37_A3.2 R38_A3.1
RF_10_A4: R36_A4.1 R37_A4.2 R38_A4.1
RF_10_A5: R36_A5.1 R37_A5.2 R38_A5.1
RF_10_A6: R36_A6.1 R37_A6.2 R38_A6.1
RF_10_A7: R36_A7.1 R37_A7.2 R38_A7.1
RF_10_A8: R36_A8.1 R37_A8.2 R38_A8.1
RF_11_A1: C32_A1.1 R37_A1.1
RF_11_A2: C32_A2.1 R37_A2.1
RF_11_A3: C32_A3.1 R37_A3.1
RF_11_A4: C32_A4.1 R37_A4.1
RF_11_A5: C32_A5.1 R37_A5.1
RF_11_A6: C32_A6.1 R37_A6.1
RF_11_A7: C32_A7.1 R37_A7.1
RF_11_A8: C32_A8.1 R37_A8.1
RF_i_A1: R36_A1.2 R41_A1.2 U6_A1.8
RF_i_A2: R36_A2.2 R41_A2.2 U6_A2.8
RF_i_A3: R36_A3.2 R41_A3.2 U6_A3.8
RF_i_A4: R36_A4.2 R41_A4.2 U6_A4.8
RF_i_A5: R36_A5.2 R41_A5.2 U6_A5.8
RF_i_A6: R36_A6.2 R41_A6.2 U6_A6.8
RF_i_A7: R36_A7.2 R41_A7.2 U6_A7.8
RF_i_A8: R36_A8.2 R41_A8.2 U6_A8.8
RF_o_A1: C31_A1.1 U5_A1.3
RF_o_A2: C31_A2.1 U5_A2.3
RF_o_A3: C31_A3.1 U5_A3.3
RF_o_A4: C31_A4.1 U5_A4.3
RF_o_A5: C31_A5.1 U5_A5.3
RF_o_A6: C31_A6.1 U5_A6.3
RF_o_A7: C31_A7.1 U5_A7.3
RF_o_A8: C31_A8.1 U5_A8.3
RFi_A1: C32_A1.2 U5_A1.6
RFi_A2: C32_A2.2 U5_A2.6
RFi_A3: C32_A3.2 U5_A3.6
RFi_A4: C32_A4.2 U5_A4.6
RFi_A5: C32_A5.2 U5_A5.6
RFi_A6: C32_A6.2 U5_A6.6
RFi_A7: C32_A7.2 U5_A7.6
RFi_A8: C32_A8.2 U5_A8.6
RFo_A1: C31_A1.2 L2_A1.1
RFo_A2: C31_A2.2 L2_A2.1
RFo_A3: C31_A3.2 L2_A3.1
RFo_A4: C31_A4.2 L2_A4.1
RFo_A5: C31_A5.2 L2_A5.1
RFo_A6: C31_A6.2 L2_A6.1
RFo_A7: C31_A7.2 L2_A7.1
RFo_A8: C31_A8.2 L2_A8.1
RFout_A1: J7_A1.1 L5_A1.2
RFout_A2: J7_A2.1 L5_A2.2
RFout_A3: J7_A3.1 L5_A3.2
RFout_A4: J7_A4.1 L5_A4.2
RFout_A5: J7_A5.1 L5_A5.2
RFout_A6: J7_A6.1 L5_A6.2
RFout_A7: J7_A7.1 L5_A7.2
RFout_A8: J7_A8.1 L5_A8.2
SCLK: U1_M1.48 U4_LS2.11
SCLK_2: U1_M2.48 U4_LS1.11
SCLK_2_L: J2.5 J5.5 J6.A17 U4_LS1.2
SCLK_L: J2.6 J4.5 J6.B17 U4_LS2.2
SDIO_0: R3_M1.2 U1_M1.50 U4_LS3.9
SDIO_0_2: R3_M2.2 U1_M2.50 U4_LS4.9
SDIO_0_2_L: J2.19 J5.15 J6.A24 U4_LS4.4
SDIO_0_L: J2.20 J4.15 J6.B24 U4_LS3.4
SDIO_1: R4_M1.2 U1_M1.51 U4_LS3.10
SDIO_1_2: R4_M2.2 U1_M2.51 U4_LS4.10
SDIO_1_2_L: J2.17 J5.13 J6.A23 U4_LS4.3
SDIO_1_L: J2.18 J4.13 J6.B23 U4_LS3.3
SDIO_2: R5_M1.2 U1_M1.52 U4_LS3.11
SDIO_2_2: R5_M2.2 U1_M2.52 U4_LS4.11
SDIO_2_2_L: J2.15 J5.11 J6.A22 U4_LS4.2
SDIO_2_L: J2.16 J4.11 J6.B22 U4_LS3.2
SDIO_3: R6_M1.2 U1_M1.53 U4_LS3.12
SDIO_3_2: R6_M2.2 U1_M2.53 U4_LS4.12
SDIO_3_2_L: J2.13 J5.9 J6.A21 U4_LS4.1
SDIO_3_L: J2.14 J4.9 J6.B21 U4_LS3.1
SYNC_CLK: J2.24 J4.19 J6.B26 U1_M1.54
SYNC_CLK_2: J2.23 J5.19 J6.A26 U1_M2.54
SYNC_IN_2: R33.1 U1_M2.1
SYNC_IN_M1: TP4.1 U1_M1.1
SYNC_OUT: R33.2 U1_M1.2
SYNC_OUT_M2: TP5.1 U1_M2.2
VccA_LS1: C5_M1.2 C5_M2.2 C8_M1.2 C8_M2.2 C11_M1.2 C11_M2.2 C24.2 C29_LS1.2 C29_LS2.2 C29_LS3.2 C29_LS4.2 C39_A1.2 C39_A2.2 C39_A3.2 C39_A4.2 C39_A5.2 C39_A6.2 C39_A7.2 C39_A8.2 C40_A1.2 C40_A2.2 C40_A3.2 C40_A4.2 C40_A5.2 C40_A6.2 C40_A7.2 C40_A8.2 F2.2 FB1_M1.1 FB1_M2.1 FB5.2 R31.2 R34_LS1.2 R34_LS2.2 R34_LS3.2 R34_LS4.2 TP3.1 U1_M1.45 U1_M1.55 U1_M2.45 U1_M2.55 U4_LS1.14 U4_LS2.14 U4_LS3.14 U4_LS4.14 U6_A1.1 U6_A2.1 U6_A3.1 U6_A4.1 U6_A5.1 U6_A6.1 U6_A7.1 U6_A8.1
VccB_LS1: C4_M1.2 C4_M2.2 C7_M1.2 C7_M2.2 C10_M1.2 C10_M2.2 C18.2 C30_LS1.2 C30_LS2.2 C30_LS3.2 C30_LS4.2 F1.2 FB3.2 FB6_A1.1 FB6_A2.1 FB6_A3.1 FB6_A4.1 FB6_A5.1 FB6_A6.1 FB6_A7.1 FB6_A8.1 R7_M1.2 R7_M2.2 R28.2 TP2.1 U1_M1.49 U1_M2.49 U4_LS1.13 U4_LS2.13 U4_LS3.13 U4_LS4.13
pads on no net: FID1.1 FID2.1 FID3.1 FID4.1 FID5.1 FID6.1 J1.5 J1.6 J2.0 J2.1 J2.2 J2.4 J2.33 J2.34 J2.35 J2.36 J2.37 J2.38 J3.17 J3.19 J6.A12 J6.A27 J6.A28 J6.A29 J6.A30 J6.A31 J6.A32 J6.B12 J6.B27 J6.B28 J6.B29 J6.B30 J6.B31 J6.B32 T1_M1.5 T1_M2.5 T3_M1.5 T3_M2.5 T4_M1.5 T4_M2.5 T5_M1.5 T5_M2.5 U2.7 U3.7

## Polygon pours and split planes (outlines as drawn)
GND on Plane_L2 (split plane): 245 vertices, not listed, extent 19.5,19.43 3977.49,3455.72
GND on Plane_L4 (split plane): 245 vertices, not listed, extent 19.5,19.43 3977.49,3455.72
GND on Plane_L5 (split plane): 245 vertices, not listed, extent 19.5,19.43 3977.49,3455.72
GND on Plane_L7 (split plane): 245 vertices, not listed, extent 19.5,19.43 3977.49,3455.72

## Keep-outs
Keep-Out Layer:
  lines w60: 30.02,3422.53 30.02,177.53 619.57,177.53 ccw(c619.57,178.05) 620.08,178.05 620.08,427.88 ; 30.02,3445.25 3967.02,3445.25 ; 614.44,462.34 cw(c649.13,462.34) 649.13,497.04 ; 1341.49,462.57 1341.49,138.28 ccw(c1342.01,138.28) 1342.01,137.77 1656.97,137.77 ccw(c1656.97,138.28) 1657.48,138.28 1657.48,392.09 ; 1489.79,-1519.71 2176.51,-1519.71 ; 3120.65,47.61 3120.65,460.4 3967.02,460.4 3967.02,3422.53

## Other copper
TOP_L1:
  text ".Layer_Name" at 1796.16,3581.55 h120
Inner_L3:
  text ".Layer_Name" at 1780.5,3582.09 h120
Inner_L6:
  text ".Layer_Name" at 1780.5,3582.09 h120
Bottom Layer_L8:
  text ".Layer_Name" at 1582.37,3582.72 h120
Plane_L2 (plane layer: these items are gaps in the copper):
  text ".Layer_Name" at 1765.05,3582.09 h120
Plane_L5 (plane layer: these items are gaps in the copper):
  text ".Layer_Name" at 1764.38,3582.22 h120
Plane_L7 (plane layer: these items are gaps in the copper):
  text ".Layer_Name" at 1764.67,3582.22 h120
Plane_L4 (plane layer: these items are gaps in the copper):
  text ".Layer_Name" at 1764.8,3582.22 h120
Multi-Layer:
  text "DDS_PCB" at 1758.35,3711.55 h120

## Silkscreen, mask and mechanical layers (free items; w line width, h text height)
Top Overlay:
  text ".Layer_Name" at 1694.32,3582.18 h120
  text "chip1" at 3200,3153.98 h78.74
  text "chip2" at 2930,3138.98 h78.74
  text "RF SW" at 2610,3135.82 h78.74
Board Layer Stack Bottom Overlay:
  drawing of 14 lines, arcs and shapes, not listed
  text ".Layer_Name" at 1162.75,3582.18 h120
  text "+12V" at 3375.02,3197.53 h100 r270
  text "GND" at 3650.02,3192.53 h100 r270
  text "Quantum Source Labs LTD." at 3710.02,1532.53 h100
  text "Board P/N: ______________" at 3705.02,1437.53 h100
  text "S/N:____________________" at 3705.02,1342.53 h100
  text "Apr. 2023" at 3710.52,1223.82 h100
Top Solder:
  text ".Layer_Name" at 1712.9,3581.55 h120
Board Layer Stack Bottom Solder:
  text ".Layer_Name" at 1181.32,3582.18 h120
Top Assembly:
  text ".Layer_Name" at 1646.55,3582.84 h120
Bottom Assembly:
  text ".Layer_Name" at 1571.62,3582.84 h120
Board:
  lines w1: 30.01,3475.78 ccw(c30.02,3445.25) 1.68,3433.89 ccw(c30.02,3422.53) -0.51,3422.53 -0.51,177.53 ccw(c30.02,177.53) 30.02,147 619.57,147 ccw(c619.57,178.05) 650.61,178.05 650.61,432.04 1310.96,432.04 1310.96,138.28 ccw(c1342.01,138.28) 1342.01,107.24 1627.63,107.24 ccw(c1627.63,138.28) 1658.67,138.28 1658.66,138.36 1658.66,391.24 cw(c1729.39,391.24) 1665.05,420.6 1665.72,420.87 cw(c1729.39,392.09) 1729.39,461.96 1729.4,461.96 cw(c1729.4,391.24) 1800.12,391.24 1800.12,20.35 1800.68,19.38 1820.63,-0.36 1821.35,-0.66 2224.05,-0.66 2224.78,-0.36 2244.61,19.47 2244.91,20.2 2244.91,322.18 cw(c2276.2,322.18) 2276.2,353.47 2283.83,353.47 cw(c2283.83,322.33) 2314.97,322.33 2314.97,20.57 2316,19.54 3108.65,19.54 ccw(c3120.65,47.61) 3132.64,19.54 3150.65,19.54 3151.68,20.57 3151.68,429.87 3967.02,429.87 ccw(c3967.02,460.4) 3997.55,460.41 3997.55,3422.53 ; 30.02,3475.78 3967.02,3475.78 cw(c3967.02,3445.25) 3997.55,3445.25 ; 30.01,3475.78 30.02,3475.78 ; 3997.55,3422.54 ccw(c3967.02,3422.53) 3995.36,3433.89 ccw(c3967.02,3445.25) 3997.55,3445.24 ; 3997.55,3422.54 3997.55,3422.53 ; 3997.55,3445.24 3997.55,3445.25
FAB_DWG_INFO:
  drawing of 637 lines, arcs and shapes, not listed
  text ".Layer_Name" at 1638.21,3591.55 h120
  text "General Notes for PCB production:" at 4645.95,3379.31 h196.85
  text "1. General:" at 4608.87,3182.26 h118.11
  text "1.1 Drill per drilling table on the drill drawing." at 4768.28,3084.27 h118.11
  text "1.2 All holes sizes are after platind." at 4768.28,2985.85 h118.11
  text "1.3 Manufacturing per IPC-6012-A (last version)." at 4768.28,2887.42 h118.11
  text "1.4 General tolerance: +/-0.2mm unless otherwise specified/" at 4768.28,2789 h118.11
  text "1.5 Hole size tolerance: +/-0.1mm +/-0.05mm, unless otherwise specified/" at 4768.28,2690.57 h118.11
  text "1.6 Each production batch/lot should be delivered with a C.O.C. and test report." at 4768.28,2592.15 h118.11
  text "2. Material:" at 4610.8,2493.72 h118.11
  text "2.1 Class epoxy FR4 Total thickness: 1.6 mm +/-10%" at 4768.28,2395.3 h118.11
  text "2.2 Material should be fire resistance and UL-94V-0 recognized." at 4768.28,2296.87 h118.11
  text "2.3.NO. OF LAYERS: 8LAYERS." at 4768.28,2198.45 h118.11
  text "3. Plating:" at 4610.8,2100.02 h118.11
  text "3.1 ROHS complieant immersion gold (gold 0.05um min.+nickel 3um min.) ,HI TG-170." at 4768.28,2001.6 h118.11
  text "3.2 All holes to be plated thru, except noted else." at 4768.28,1903.17 h118.11
  text "4. Solder mask:" at 4610.8,1804.75 h118.11
  text "4.1 Solder mask per IPC-SM-840M." at 4768.28,1706.32 h118.11
  text "4.2 Solder mask type:wet photoimageable class 2, color green on both sides of the board." at 4768.28,1607.9 h118.11
  text "4.3 Solder mask over copper to cover all traces completety." at 4768.28,1509.47 h118.11
  text "5.1 All the markings on the board should be with proxy ink, both sides unless otherwise." at 4773.28,1299.2 h118.11
  text "5.2 Board to be marked with manufacturing code which mets U.L.  flammability rating 94V-0, or better." at 4773.28,1200.77 h118.11
  text "5.3 E.S.D. symbol to be marked with yellow / white epoxy ink." at 4773.28,1102.35 h118.11
  text "6. Final test:" at 4615.8,1003.92 h118.11
  text "6.1 Each board to be visual and mechanical tested per IPC-A-600 class 2 workmanship standart." at 4773.28,905.49 h118.11
  text "6.2 Bow and twist per IPC-TM-650 wrap age shall not exceed 0.75%," at 4773.28,807.07 h118.11
  text "each board must be measured on each corner." at 4989.81,708.64 h118.11
  text "Symbol" at 4937.5,237.5 h72
  text "Count" at 5443.38,237.5 h72
  text "Hole Size" at 6033.22,237.5 h72
  text "Plated" at 7182.88,237.5 h72
  text "DETAIL A" at 3700.74,141.82 h125
  text "1" at 5443.38,87.5 h60
  text "95.67mil (2.430mm)" at 6033.22,87.5 h60
  text "PTH" at 7182.88,87.5 h60
  text "2" at 5443.38,-62.5 h60
  text "62.99mil (1.600mm)" at 6033.22,-62.5 h60
  text "NPTH" at 7182.88,-62.5 h60
  text "4" at 5443.38,-212.5 h60
  text "47.24mil (1.200mm)" at 6033.22,-212.5 h60
  text "PTH" at 7182.88,-212.5 h60
  text "4" at 5443.38,-362.5 h60
  text "125.98mil (3.200mm)" at 6033.22,-362.5 h60
  text "PTH" at 7182.88,-362.5 h60
  text "5" at 5443.38,-512.5 h60
  text "33.86mil (0.860mm)" at 6033.22,-512.5 h60
  text "PTH" at 7182.88,-512.5 h60
  text "18" at 5443.38,-662.5 h60
  text "8.00mil (0.203mm)" at 6033.22,-662.5 h60
  text "PTH" at 7182.88,-662.5 h60
  text "40" at 5443.38,-812.5 h60
  text "33.07mil (0.840mm)" at 6033.22,-812.5 h60
  text "PTH" at 7182.88,-812.5 h60
  text "20" at 2668.67,-949.02 h50
  text "40" at 5443.38,-962.5 h60
  text "63.00mil (1.600mm)" at 6033.22,-962.5 h60
  text "PTH" at 7182.88,-962.5 h60
  text "+/- 5" at 2632.56,-1015.75 h31
  text "60" at 5443.38,-1112.5 h60
  text "43.31mil (1.100mm)" at 6033.22,-1112.5 h60
  text "PTH" at 7182.88,-1112.5 h60
  text "1.57" at 1038.67,-1162.02 h50
  text "MAX OVER PLATING" at 1286.74,-1165.23 h50
  text "174 Total" at 5443.38,-1262.5 h60
  text "0.062" at 1122.17,-1345.52 h50
  text "[" at 1049.82,-1370.55 h125
  text "]" at 1332.56,-1372.28 h125
  text "Layer" at 4822.5,-1497.5 h60
  text "Name" at 5232.41,-1497.5 h60
  text "Material" at 7231.81,-1497.5 h60
  text "Thickness" at 8091.58,-1497.5 h60
  text "Constant" at 8741.41,-1497.5 h60
  text "Board Layer Stack" at 9311.27,-1497.5 h60
  text "Top Overlay" at 5232.41,-1617.5 h60
  text "Top Solder" at 5232.41,-1737.5 h60
  text "Solder Resist" at 7231.81,-1737.5 h60
  text "0.40mil" at 8091.58,-1737.5 h60
  text "3.5" at 8741.41,-1737.5 h60
  text "1" at 4822.5,-1857.5 h60
  text "TOP_L1" at 5232.41,-1857.5 h60
  text "0.60mil" at 8091.58,-1857.5 h60
  text "Dielectric1" at 5232.41,-1977.5 h60
  text "FR-4" at 7231.81,-1977.5 h60
  text "2.90mil" at 8091.58,-1977.5 h60
  text "3.2" at 8741.41,-1977.5 h60
  text "2" at 4822.5,-2097.5 h60
  text "Plane_L2" at 5232.41,-2097.5 h60
  text "0.70mil" at 8091.58,-2097.5 h60
  text "Dielectric7" at 5232.41,-2217.5 h60
  text "FR-4" at 7231.81,-2217.5 h60
  text "3.00mil" at 8091.58,-2217.5 h60
  text "3.3" at 8741.41,-2217.5 h60
  text "3" at 4822.5,-2337.5 h60
  text "Inner_L3" at 5232.41,-2337.5 h60
  text "0.70mil" at 8091.58,-2337.5 h60
  text "Dielectric4" at 5232.41,-2457.5 h60
  text "FR-4" at 7231.81,-2457.5 h60
  text "2.80mil" at 8091.58,-2457.5 h60
  text "3.1" at 8741.41,-2457.5 h60
  text "+0,25" at 917.56,-2525.75 h31
  text "1,3" at 669.67,-2578.02 h50
  text "4" at 4822.5,-2577.5 h60
  text "Plane_L4" at 5232.41,-2577.5 h60
  text "1.20mil" at 8091.58,-2577.5 h60
  text "-0,25" at 917.56,-2614.33 h31
  text "Dielectric10" at 5232.41,-2697.5 h60
  text "FR-4" at 7231.81,-2697.5 h60
  text "3.00mil" at 8091.58,-2697.5 h60
  text "3.3" at 8741.41,-2697.5 h60
  text "+,010" at 921.71,-2742.28 h31
  text "0,051" at 628.67,-2795.02 h50
  text "5" at 4822.5,-2817.5 h60
  text "Plane_L5" at 5232.41,-2817.5 h60
  text "1.20mil" at 8091.58,-2817.5 h60
  text "-,010" at 921.71,-2830.87 h31
  text "[" at 536.85,-2833.99 h125
  text "]" at 1093.93,-2833.99 h125
  text "Dielectric 1" at 5232.41,-2937.5 h60
  text "FR-4" at 7231.81,-2937.5 h60
  text "2.80mil" at 8091.58,-2937.5 h60
  text "3.1" at 8741.41,-2937.5 h60
  text "6" at 4822.5,-3057.5 h60
  text "Inner_L6" at 5232.41,-3057.5 h60
  text "0.70mil" at 8091.58,-3057.5 h60
  text "DETAIL A" at 1593.92,-3104.29 h125
  text "Dielectric 6" at 5232.41,-3177.5 h60
  text "FR-4" at 7231.81,-3177.5 h60
  text "3.00mil" at 8091.58,-3177.5 h60
  text "3.3" at 8741.41,-3177.5 h60
  text "7" at 4822.5,-3297.5 h60
  text "Plane_L7" at 5232.41,-3297.5 h60
  text "0.70mil" at 8091.58,-3297.5 h60
  text "Dielectric 7" at 5232.41,-3417.5 h60
  text "FR-4" at 7231.81,-3417.5 h60
  text "2.90mil" at 8091.58,-3417.5 h60
  text "3.2" at 8741.41,-3417.5 h60
  text "8" at 4822.5,-3537.5 h60
  text "Bottom Layer_L8" at 5232.41,-3537.5 h60
  text "0.60mil" at 8091.58,-3537.5 h60
  text "Board Layer Stack Bottom Solder" at 5232.41,-3657.5 h60
  text "Solder Resist" at 7231.81,-3657.5 h60
  text "0.40mil" at 8091.58,-3657.5 h60
  text "3.5" at 8741.41,-3657.5 h60
  text "Board Layer Stack Bottom Overlay" at 5232.41,-3777.5 h60
FAB:
  lines w10: 8079.29,473.91 8079.29,4372.91

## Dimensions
29.02,256.27 to 3967.02,3475.78 on FAB_DWG_INFO
29.02,335.01 to 3997.55,3422.54 on FAB_DWG_INFO
29.02,295.64 to 3997.55,3422.53 on FAB_DWG_INFO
